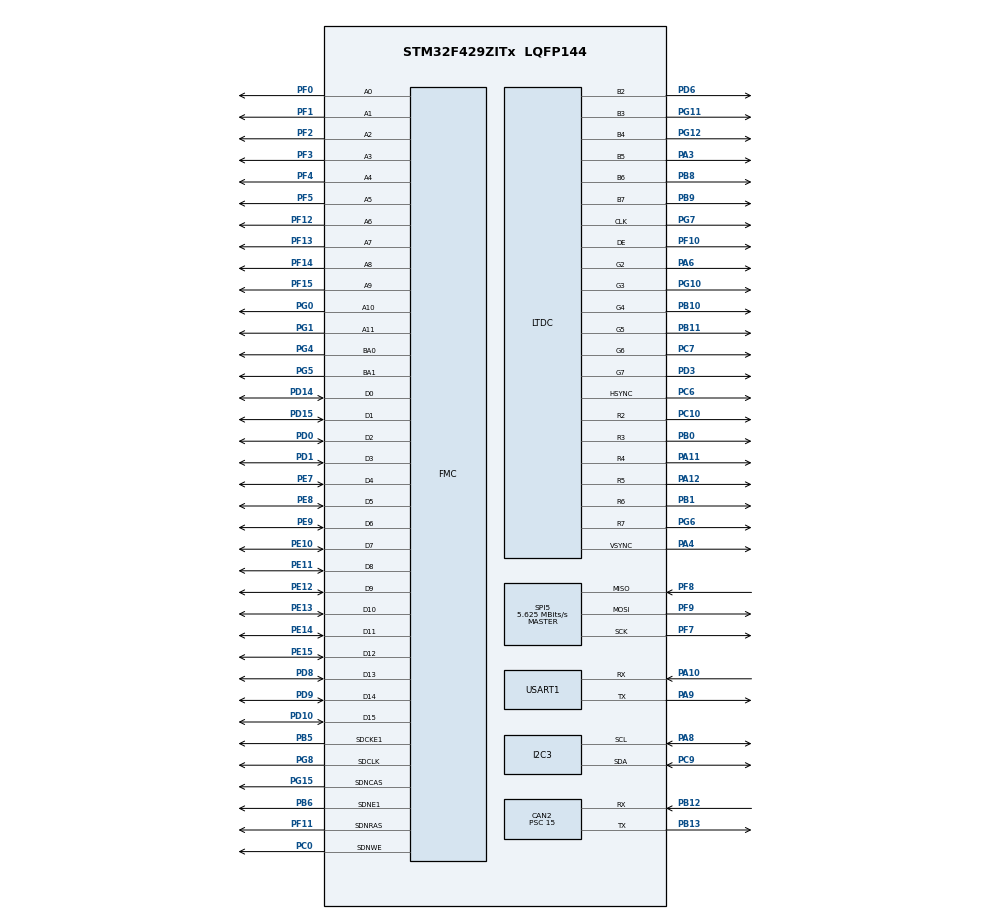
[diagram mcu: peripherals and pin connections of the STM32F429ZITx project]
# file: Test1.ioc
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CAN2.BS1=CAN_BS1_2TQ
CAN2.BS2=CAN_BS2_3TQ
CAN2.CalculateBaudRate=500000
CAN2.CalculateTimeBit=2000
CAN2.CalculateTimeQuantum=333.3333333333333
CAN2.Mode=CAN_MODE_LOOPBACK
CAN2.Prescaler=15
CAN2.SJW=CAN_SJW_4TQ
DMA2D.ColorMode=DMA2D_OUTPUT_RGB565
FMC.CASLatency1=FMC_SDRAM_CAS_LATENCY_3
FMC.ExitSelfRefreshDelay1=7
FMC.LoadToActiveDelay1=2
FMC.RCDDelay1=2
FMC.RPDelay1=2
FMC.RPDelay2=2
FMC.ReadPipeDelay1=FMC_SDRAM_RPIPE_DELAY_1
FMC.ReadPipeDelay2=FMC_SDRAM_RPIPE_DELAY_1
FMC.RowCycleDelay1=7
FMC.RowCycleDelay2=7
FMC.SDClockPeriod1=FMC_SDRAM_CLOCK_PERIOD_2
FMC.SDClockPeriod2=FMC_SDRAM_CLOCK_PERIOD_2
FMC.SelfRefreshTime1=4
FMC.WriteRecoveryTime1=3
LTDC.ActiveH=320
LTDC.ActiveW=240
LTDC.HBP=20
LTDC.HFP=10
LTDC.HSync=10
LTDC.VFP=4
LTDC.VSync=2
Mcu.Family=STM32F4
Mcu.Name=STM32F429ZITx
Mcu.Package=LQFP144
NVIC.CAN2_RX0_IRQn=true\:1\:0\:true\:false\:true\:true\:true\:true
NVIC.CAN2_RX1_IRQn=true\:1\:0\:true\:false\:true\:true\:true\:true
NVIC.DMA2D_IRQn=true\:2\:0\:true\:false\:true\:true\:true\:true
NVIC.LTDC_ER_IRQn=true\:2\:0\:true\:false\:true\:true\:true\:true
NVIC.LTDC_IRQn=true\:2\:0\:true\:false\:true\:true\:true\:true
NVIC.PriorityGroup=NVIC_PRIORITYGROUP_4
PA10.Mode=Asynchronous
PA10.Signal=USART1_RX
PA11.Mode=RGB666
PA11.Signal=LTDC_R4
PA12.Mode=RGB666
PA12.Signal=LTDC_R5
PA3.Mode=RGB666
PA3.Signal=LTDC_B5
PA4.Mode=RGB666
PA4.Signal=LTDC_VSYNC
PA6.Mode=RGB666
PA6.Signal=LTDC_G2
PA8.Mode=I2C
PA8.Signal=I2C3_SCL
PA9.Mode=Asynchronous
PA9.Signal=USART1_TX
PB0.Mode=RGB666
PB0.Signal=LTDC_R3
PB1.Mode=RGB666
PB1.Signal=LTDC_R6
PB10.Mode=RGB666
PB10.Signal=LTDC_G4
PB11.Mode=RGB666
PB11.Signal=LTDC_G5
PB12.Mode=CAN_Activate
PB12.Signal=CAN2_RX
PB13.Mode=CAN_Activate
PB13.Signal=CAN2_TX
PB5.Mode=SdramChipSelect2_1
PB5.Signal=FMC_SDCKE1
PB6.Mode=SdramChipSelect2_1
PB6.Signal=FMC_SDNE1
PB8.Mode=RGB666
PB8.Signal=LTDC_B6
PB9.Mode=RGB666
PB9.Signal=LTDC_B7
PC0.Signal=FMC_SDNWE
PC10.Mode=RGB666
PC10.Signal=LTDC_R2
PC6.Mode=RGB666
PC6.Signal=LTDC_HSYNC
PC7.Mode=RGB666
PC7.Signal=LTDC_G6
PC9.Mode=I2C
PC9.Signal=I2C3_SDA
PD0.Signal=FMC_D2_DA2
PD1.Signal=FMC_D3_DA3
PD10.Signal=FMC_D15_DA15
PD14.Signal=FMC_D0_DA0
PD15.Signal=FMC_D1_DA1
PD3.Mode=RGB666
PD3.Signal=LTDC_G7
PD6.Mode=RGB666
PD6.Signal=LTDC_B2
PD8.Signal=FMC_D13_DA13
PD9.Signal=FMC_D14_DA14
PE10.Signal=FMC_D7_DA7
PE11.Signal=FMC_D8_DA8
PE12.Signal=FMC_D9_DA9
PE13.Signal=FMC_D10_DA10
PE14.Signal=FMC_D11_DA11
PE15.Signal=FMC_D12_DA12
PE7.Signal=FMC_D4_DA4
PE8.Signal=FMC_D5_DA5
PE9.Signal=FMC_D6_DA6
PF0.Signal=FMC_A0
PF1.Signal=FMC_A1
PF10.Mode=RGB666
PF10.Signal=LTDC_DE
PF11.Signal=FMC_SDNRAS
PF12.Signal=FMC_A6
PF13.Signal=FMC_A7
PF14.Signal=FMC_A8
PF15.Signal=FMC_A9
PF2.Signal=FMC_A2
PF3.Signal=FMC_A3
PF4.Signal=FMC_A4
PF5.Signal=FMC_A5
PF7.Mode=Full_Duplex_Master
PF7.Signal=SPI5_SCK
PF8.Mode=Full_Duplex_Master
PF8.Signal=SPI5_MISO
PF9.Mode=Full_Duplex_Master
PF9.Signal=SPI5_MOSI
PG0.Signal=FMC_A10
PG1.Signal=FMC_A11
PG10.Mode=RGB666
PG10.Signal=LTDC_G3
PG11.Mode=RGB666
PG11.Signal=LTDC_B3
PG12.Mode=RGB666
PG12.Signal=LTDC_B4
PG15.Signal=FMC_SDNCAS
PG4.Signal=FMC_A14_BA0
PG5.Signal=FMC_A15_BA1
PG6.Mode=RGB666
PG6.Signal=LTDC_R7
PG7.Mode=RGB666
PG7.Signal=LTDC_CLK
PG8.Signal=FMC_SDCLK
PH0/OSC_IN.Mode=HSE-External-Oscillator
PH0/OSC_IN.Signal=RCC_OSC_IN
PH1/OSC_OUT.Mode=HSE-External-Oscillator
PH1/OSC_OUT.Signal=RCC_OSC_OUT
ProjectManager.HeapSize=0x200
ProjectManager.StackSize=0x400
ProjectManager.TargetToolchain=STM32CubeIDE
RCC.48MHZClocksFreq_Value=120000000
RCC.AHBFreq_Value=180000000
RCC.APB1CLKDivider=RCC_HCLK_DIV4
RCC.APB1Freq_Value=45000000
RCC.APB1TimFreq_Value=90000000
RCC.APB2CLKDivider=RCC_HCLK_DIV2
RCC.APB2Freq_Value=90000000
RCC.APB2TimFreq_Value=180000000
RCC.CortexFreq_Value=180000000
RCC.HCLKFreq_Value=180000000
RCC.HSE_VALUE=8000000
RCC.HSI_VALUE=16000000
RCC.LSE_VALUE=32768
RCC.PLLN=180
RCC.PLLQ=3
RCC.PLLSAIN=52
RCC.PLLSAIR=4
RCC.PLLSourceVirtual=RCC_PLLSOURCE_HSE
RCC.SYSCLKFreq_VALUE=180000000
RCC.SYSCLKSource=RCC_SYSCLKSOURCE_PLLCLK
RCC.VCOOutputFreq_Value=360000000
SH.FMC_A0.0=FMC_A0,12b-sda1
SH.FMC_A1.0=FMC_A1,12b-sda1
SH.FMC_A10.0=FMC_A10,12b-sda1
SH.FMC_A11.0=FMC_A11,12b-sda1
SH.FMC_A14_BA0.0=FMC_BA0,FourSdramBanks1
SH.FMC_A15_BA1.0=FMC_BA1,FourSdramBanks1
SH.FMC_A2.0=FMC_A2,12b-sda1
SH.FMC_A3.0=FMC_A3,12b-sda1
SH.FMC_A4.0=FMC_A4,12b-sda1
SH.FMC_A5.0=FMC_A5,12b-sda1
SH.FMC_A6.0=FMC_A6,12b-sda1
SH.FMC_A7.0=FMC_A7,12b-sda1
SH.FMC_A8.0=FMC_A8,12b-sda1
SH.FMC_A9.0=FMC_A9,12b-sda1
SH.FMC_D0_DA0.0=FMC_D0,sd-16b-d1
SH.FMC_D10_DA10.0=FMC_D10,sd-16b-d1
SH.FMC_D11_DA11.0=FMC_D11,sd-16b-d1
SH.FMC_D12_DA12.0=FMC_D12,sd-16b-d1
SH.FMC_D13_DA13.0=FMC_D13,sd-16b-d1
SH.FMC_D14_DA14.0=FMC_D14,sd-16b-d1
SH.FMC_D15_DA15.0=FMC_D15,sd-16b-d1
SH.FMC_D1_DA1.0=FMC_D1,sd-16b-d1
SH.FMC_D2_DA2.0=FMC_D2,sd-16b-d1
SH.FMC_D3_DA3.0=FMC_D3,sd-16b-d1
SH.FMC_D4_DA4.0=FMC_D4,sd-16b-d1
SH.FMC_D5_DA5.0=FMC_D5,sd-16b-d1
SH.FMC_D6_DA6.0=FMC_D6,sd-16b-d1
SH.FMC_D7_DA7.0=FMC_D7,sd-16b-d1
SH.FMC_D8_DA8.0=FMC_D8,sd-16b-d1
SH.FMC_D9_DA9.0=FMC_D9,sd-16b-d1
SH.FMC_SDCLK.0=FMC_SDCLK,12b-sda1
SH.FMC_SDNCAS.0=FMC_SDNCAS,12b-sda1
SH.FMC_SDNRAS.0=FMC_SDNRAS,12b-sda1
SH.FMC_SDNWE.0=FMC_SDNWE,12b-sda1
SPI5.BaudRatePrescaler=SPI_BAUDRATEPRESCALER_16
SPI5.CalculateBaudRate=5.625 MBits/s
SPI5.Direction=SPI_DIRECTION_2LINES
SPI5.Mode=SPI_MODE_MASTER
SPI5.VirtualType=VM_MASTER
USART1.VirtualMode=VM_ASYNC
VP_DMA2D_VS_DMA2D.Mode=DMA2D_Activate
board=STM32F429I-DISC1

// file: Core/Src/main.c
/* USER CODE BEGIN Header */
/**
  ******************************************************************************
  * @file           : main.c
  * @brief          : Main program body
  ******************************************************************************
  * @attention
  *
  * Copyright (c) 2023 STMicroelectronics.
  * All rights reserved.
  *
  * This software is licensed under terms that can be found in the LICENSE file
  * in the root directory of this software component.
  * If no LICENSE file comes with this software, it is provided AS-IS.
  *
  ******************************************************************************
  */
/* USER CODE END Header */
#include "main.h"

/* USER CODE BEGIN Includes */
#include "stm32f429i_discovery_lcd.h"
#include "image.h"
/* USER CODE END Includes */

CAN_HandleTypeDef hcan2;

DMA2D_HandleTypeDef hdma2d;

I2C_HandleTypeDef hi2c3;

LTDC_HandleTypeDef hltdc;

SPI_HandleTypeDef hspi5;

UART_HandleTypeDef huart1;

SDRAM_HandleTypeDef hsdram1;

void SystemClock_Config(void);
static void MX_GPIO_Init(void);
static void MX_DMA2D_Init(void);
static void MX_FMC_Init(void);
static void MX_I2C3_Init(void);
static void MX_LTDC_Init(void);
static void MX_SPI5_Init(void);
static void MX_USART1_UART_Init(void);
static void MX_CAN2_Init(void);

/* USER CODE BEGIN 0 */
CAN_TxHeaderTypeDef TxHeader;
CAN_RxHeaderTypeDef RxHeader;

uint8_t TxData[8] = { 'X' , 'A' , 'T' , 'F', 'D' , 'D' , 'G' , 'D' };

uint8_t RxData[8];

uint32_t TxMailbox;

void HAL_CAN_RxFifo0MsgPendingCallback(CAN_HandleTypeDef *hcan)
{
	HAL_CAN_GetRxMessage(&hcan2, CAN_RX_FIFO0, &RxHeader, RxData);
}

/* USER CODE END 0 */

int main(void)
{

  /* MCU Configuration--------------------------------------------------------*/

  /* Reset of all peripherals, Initializes the Flash interface and the Systick. */
  HAL_Init();

  /* Configure the system clock */
  SystemClock_Config();

  /* Initialize all configured peripherals */
  MX_GPIO_Init();
  MX_DMA2D_Init();
  MX_FMC_Init();
  MX_I2C3_Init();
  MX_LTDC_Init();
  MX_SPI5_Init();
  MX_USART1_UART_Init();
  MX_CAN2_Init();
  /* USER CODE BEGIN 2 */

	HAL_CAN_Start(&hcan2);

	  // Activate the notification
	HAL_CAN_ActivateNotification(&hcan2, CAN_IT_RX_FIFO0_MSG_PENDING);

	TxHeader.DLC = 8;  // data length
	TxHeader.IDE = CAN_ID_STD;
	TxHeader.StdId = 0x407;  // ID

	BSP_LCD_Init();
	BSP_LCD_LayerDefaultInit(LCD_BACKGROUND_LAYER,LCD_FRAME_BUFFER);
	BSP_LCD_LayerDefaultInit(LCD_FOREGROUND_LAYER,LCD_FRAME_BUFFER);
	BSP_LCD_SelectLayer(LCD_FOREGROUND_LAYER);
	BSP_LCD_SetFont(&Font20);
	BSP_LCD_DisplayOn();
	BSP_LCD_Clear(LCD_COLOR_BLUE);

	BSP_LCD_SetTextColor(LCD_COLOR_RED);
	BSP_LCD_DisplayStringAt(1 , 125 ,(uint8_t *) "CAN DATA:",LEFT_MODE);

	uint16_t x = 24;
  /* USER CODE END 2 */

  /* Infinite loop */
  while (1)
  {

    /* USER CODE BEGIN 3 */
	  HAL_CAN_AddTxMessage(&hcan2, &TxHeader, TxData, &TxMailbox);
	  BSP_LCD_SetTextColor(LCD_COLOR_RED);
	  for (uint32_t i = 0; i < 8 ; i ++)
	  {
		  BSP_LCD_DisplayChar (x , 150 , RxData[i]);
		  x+= 24;
	  }
	  x = 24;

  }
  /* USER CODE END 3 */
}

void SystemClock_Config(void)
{
  RCC_OscInitTypeDef RCC_OscInitStruct = {0};
  RCC_ClkInitTypeDef RCC_ClkInitStruct = {0};

  /** Configure the main internal regulator output voltage
  */
  __HAL_RCC_PWR_CLK_ENABLE();
  __HAL_PWR_VOLTAGESCALING_CONFIG(PWR_REGULATOR_VOLTAGE_SCALE1);

  /** Initializes the RCC Oscillators according to the specified parameters
  * in the RCC_OscInitTypeDef structure.
  */
  RCC_OscInitStruct.OscillatorType = RCC_OSCILLATORTYPE_HSE;
  RCC_OscInitStruct.HSEState = RCC_HSE_ON;
  RCC_OscInitStruct.PLL.PLLState = RCC_PLL_ON;
  RCC_OscInitStruct.PLL.PLLSource = RCC_PLLSOURCE_HSE;
  RCC_OscInitStruct.PLL.PLLM = 16;
  RCC_OscInitStruct.PLL.PLLN = 180;
  RCC_OscInitStruct.PLL.PLLP = RCC_PLLP_DIV2;
  RCC_OscInitStruct.PLL.PLLQ = 3;
  if (HAL_RCC_OscConfig(&RCC_OscInitStruct) != HAL_OK)
  {
    Error_Handler();
  }

  /** Activate the Over-Drive mode
  */
  if (HAL_PWREx_EnableOverDrive() != HAL_OK)
  {
    Error_Handler();
  }

  /** Initializes the CPU, AHB and APB buses clocks
  */
  RCC_ClkInitStruct.ClockType = RCC_CLOCKTYPE_HCLK|RCC_CLOCKTYPE_SYSCLK
                              |RCC_CLOCKTYPE_PCLK1|RCC_CLOCKTYPE_PCLK2;
  RCC_ClkInitStruct.SYSCLKSource = RCC_SYSCLKSOURCE_PLLCLK;
  RCC_ClkInitStruct.AHBCLKDivider = RCC_SYSCLK_DIV1;
  RCC_ClkInitStruct.APB1CLKDivider = RCC_HCLK_DIV4;
  RCC_ClkInitStruct.APB2CLKDivider = RCC_HCLK_DIV2;

  if (HAL_RCC_ClockConfig(&RCC_ClkInitStruct, FLASH_LATENCY_5) != HAL_OK)
  {
    Error_Handler();
  }
}

static void MX_CAN2_Init(void)
{

  hcan2.Instance = CAN2;
  hcan2.Init.Prescaler = 15;
  hcan2.Init.Mode = CAN_MODE_LOOPBACK;
  hcan2.Init.SyncJumpWidth = CAN_SJW_4TQ;
  hcan2.Init.TimeSeg1 = CAN_BS1_2TQ;
  hcan2.Init.TimeSeg2 = CAN_BS2_3TQ;
  hcan2.Init.TimeTriggeredMode = DISABLE;
  hcan2.Init.AutoBusOff = DISABLE;
  hcan2.Init.AutoWakeUp = DISABLE;
  hcan2.Init.AutoRetransmission = DISABLE;
  hcan2.Init.ReceiveFifoLocked = DISABLE;
  hcan2.Init.TransmitFifoPriority = DISABLE;
  if (HAL_CAN_Init(&hcan2) != HAL_OK)
  {
    Error_Handler();
  }
  /* USER CODE BEGIN CAN2_Init 2 */
  CAN_FilterTypeDef canfilterconfig;

  canfilterconfig.FilterActivation = CAN_FILTER_ENABLE;
  canfilterconfig.FilterBank = 18;  // which filter bank to use from the assigned ones
  canfilterconfig.FilterFIFOAssignment = CAN_FILTER_FIFO0;
  canfilterconfig.FilterIdHigh = 0x407<<5;
  canfilterconfig.FilterIdLow = 0;
  canfilterconfig.FilterMaskIdHigh = 0x407<<5;
  canfilterconfig.FilterMaskIdLow = 0x0000;
  canfilterconfig.FilterMode = CAN_FILTERMODE_IDMASK;
  canfilterconfig.FilterScale = CAN_FILTERSCALE_32BIT;
 // canfilterconfig.SlaveStartFilterBank = 20;  // how many filters to assign to the CAN1 (master can)

  HAL_CAN_ConfigFilter(&hcan2, &canfilterconfig);
  /* USER CODE END CAN2_Init 2 */

}

static void MX_DMA2D_Init(void)
{

  hdma2d.Instance = DMA2D;
  hdma2d.Init.Mode = DMA2D_M2M;
  hdma2d.Init.ColorMode = DMA2D_OUTPUT_RGB565;
  hdma2d.Init.OutputOffset = 0;
  hdma2d.LayerCfg[1].InputOffset = 0;
  hdma2d.LayerCfg[1].InputColorMode = DMA2D_INPUT_RGB565;
  hdma2d.LayerCfg[1].AlphaMode = DMA2D_NO_MODIF_ALPHA;
  hdma2d.LayerCfg[1].InputAlpha = 0;
  if (HAL_DMA2D_Init(&hdma2d) != HAL_OK)
  {
    Error_Handler();
  }
  if (HAL_DMA2D_ConfigLayer(&hdma2d, 1) != HAL_OK)
  {
    Error_Handler();
  }

}

static void MX_I2C3_Init(void)
{

  hi2c3.Instance = I2C3;
  hi2c3.Init.ClockSpeed = 100000;
  hi2c3.Init.DutyCycle = I2C_DUTYCYCLE_2;
  hi2c3.Init.OwnAddress1 = 0;
  hi2c3.Init.AddressingMode = I2C_ADDRESSINGMODE_7BIT;
  hi2c3.Init.DualAddressMode = I2C_DUALADDRESS_DISABLE;
  hi2c3.Init.OwnAddress2 = 0;
  hi2c3.Init.GeneralCallMode = I2C_GENERALCALL_DISABLE;
  hi2c3.Init.NoStretchMode = I2C_NOSTRETCH_DISABLE;
  if (HAL_I2C_Init(&hi2c3) != HAL_OK)
  {
    Error_Handler();
  }

  /** Configure Analogue filter
  */
  if (HAL_I2CEx_ConfigAnalogFilter(&hi2c3, I2C_ANALOGFILTER_ENABLE) != HAL_OK)
  {
    Error_Handler();
  }

  /** Configure Digital filter
  */
  if (HAL_I2CEx_ConfigDigitalFilter(&hi2c3, 0) != HAL_OK)
  {
    Error_Handler();
  }

}

static void MX_LTDC_Init(void)
{

  LTDC_LayerCfgTypeDef pLayerCfg = {0};
  LTDC_LayerCfgTypeDef pLayerCfg1 = {0};

  hltdc.Instance = LTDC;
  hltdc.Init.HSPolarity = LTDC_HSPOLARITY_AL;
  hltdc.Init.VSPolarity = LTDC_VSPOLARITY_AL;
  hltdc.Init.DEPolarity = LTDC_DEPOLARITY_AL;
  hltdc.Init.PCPolarity = LTDC_PCPOLARITY_IPC;
  hltdc.Init.HorizontalSync = 9;
  hltdc.Init.VerticalSync = 1;
  hltdc.Init.AccumulatedHBP = 29;
  hltdc.Init.AccumulatedVBP = 3;
  hltdc.Init.AccumulatedActiveW = 269;
  hltdc.Init.AccumulatedActiveH = 323;
  hltdc.Init.TotalWidth = 279;
  hltdc.Init.TotalHeigh = 327;
  hltdc.Init.Backcolor.Blue = 0;
  hltdc.Init.Backcolor.Green = 0;
  hltdc.Init.Backcolor.Red = 0;
  if (HAL_LTDC_Init(&hltdc) != HAL_OK)
  {
    Error_Handler();
  }
  pLayerCfg.WindowX0 = 0;
  pLayerCfg.WindowX1 = 0;
  pLayerCfg.WindowY0 = 0;
  pLayerCfg.WindowY1 = 0;
  pLayerCfg.PixelFormat = LTDC_PIXEL_FORMAT_ARGB8888;
  pLayerCfg.Alpha = 0;
  pLayerCfg.Alpha0 = 0;
  pLayerCfg.BlendingFactor1 = LTDC_BLENDING_FACTOR1_CA;
  pLayerCfg.BlendingFactor2 = LTDC_BLENDING_FACTOR2_CA;
  pLayerCfg.FBStartAdress = 0;
  pLayerCfg.ImageWidth = 0;
  pLayerCfg.ImageHeight = 0;
  pLayerCfg.Backcolor.Blue = 0;
  pLayerCfg.Backcolor.Green = 0;
  pLayerCfg.Backcolor.Red = 0;
  if (HAL_LTDC_ConfigLayer(&hltdc, &pLayerCfg, 0) != HAL_OK)
  {
    Error_Handler();
  }
  pLayerCfg1.WindowX0 = 0;
  pLayerCfg1.WindowX1 = 0;
  pLayerCfg1.WindowY0 = 0;
  pLayerCfg1.WindowY1 = 0;
  pLayerCfg1.PixelFormat = LTDC_PIXEL_FORMAT_ARGB8888;
  pLayerCfg1.Alpha = 0;
  pLayerCfg1.Alpha0 = 0;
  pLayerCfg1.BlendingFactor1 = LTDC_BLENDING_FACTOR1_CA;
  pLayerCfg1.BlendingFactor2 = LTDC_BLENDING_FACTOR2_CA;
  pLayerCfg1.FBStartAdress = 0;
  pLayerCfg1.ImageWidth = 0;
  pLayerCfg1.ImageHeight = 0;
  pLayerCfg1.Backcolor.Blue = 0;
  pLayerCfg1.Backcolor.Green = 0;
  pLayerCfg1.Backcolor.Red = 0;
  if (HAL_LTDC_ConfigLayer(&hltdc, &pLayerCfg1, 1) != HAL_OK)
  {
    Error_Handler();
  }

}

static void MX_SPI5_Init(void)
{

  /* SPI5 parameter configuration*/
  hspi5.Instance = SPI5;
  hspi5.Init.Mode = SPI_MODE_MASTER;
  hspi5.Init.Direction = SPI_DIRECTION_2LINES;
  hspi5.Init.DataSize = SPI_DATASIZE_8BIT;
  hspi5.Init.CLKPolarity = SPI_POLARITY_LOW;
  hspi5.Init.CLKPhase = SPI_PHASE_1EDGE;
  hspi5.Init.NSS = SPI_NSS_SOFT;
  hspi5.Init.BaudRatePrescaler = SPI_BAUDRATEPRESCALER_16;
  hspi5.Init.FirstBit = SPI_FIRSTBIT_MSB;
  hspi5.Init.TIMode = SPI_TIMODE_DISABLE;
  hspi5.Init.CRCCalculation = SPI_CRCCALCULATION_DISABLE;
  hspi5.Init.CRCPolynomial = 10;
  if (HAL_SPI_Init(&hspi5) != HAL_OK)
  {
    Error_Handler();
  }

}

static void MX_USART1_UART_Init(void)
{

  huart1.Instance = USART1;
  huart1.Init.BaudRate = 115200;
  huart1.Init.WordLength = UART_WORDLENGTH_8B;
  huart1.Init.StopBits = UART_STOPBITS_1;
  huart1.Init.Parity = UART_PARITY_NONE;
  huart1.Init.Mode = UART_MODE_TX_RX;
  huart1.Init.HwFlowCtl = UART_HWCONTROL_NONE;
  huart1.Init.OverSampling = UART_OVERSAMPLING_16;
  if (HAL_UART_Init(&huart1) != HAL_OK)
  {
    Error_Handler();
  }

}

/* FMC initialization function */
static void MX_FMC_Init(void)
{

  FMC_SDRAM_TimingTypeDef SdramTiming = {0};

  /** Perform the SDRAM1 memory initialization sequence
  */
  hsdram1.Instance = FMC_SDRAM_DEVICE;
  /* hsdram1.Init */
  hsdram1.Init.SDBank = FMC_SDRAM_BANK2;
  hsdram1.Init.ColumnBitsNumber = FMC_SDRAM_COLUMN_BITS_NUM_8;
  hsdram1.Init.RowBitsNumber = FMC_SDRAM_ROW_BITS_NUM_12;
  hsdram1.Init.MemoryDataWidth = FMC_SDRAM_MEM_BUS_WIDTH_16;
  hsdram1.Init.InternalBankNumber = FMC_SDRAM_INTERN_BANKS_NUM_4;
  hsdram1.Init.CASLatency = FMC_SDRAM_CAS_LATENCY_3;
  hsdram1.Init.WriteProtection = FMC_SDRAM_WRITE_PROTECTION_DISABLE;
  hsdram1.Init.SDClockPeriod = FMC_SDRAM_CLOCK_PERIOD_2;
  hsdram1.Init.ReadBurst = FMC_SDRAM_RBURST_DISABLE;
  hsdram1.Init.ReadPipeDelay = FMC_SDRAM_RPIPE_DELAY_1;
  /* SdramTiming */
  SdramTiming.LoadToActiveDelay = 2;
  SdramTiming.ExitSelfRefreshDelay = 7;
  SdramTiming.SelfRefreshTime = 4;
  SdramTiming.RowCycleDelay = 7;
  SdramTiming.WriteRecoveryTime = 3;
  SdramTiming.RPDelay = 2;
  SdramTiming.RCDDelay = 2;

  if (HAL_SDRAM_Init(&hsdram1, &SdramTiming) != HAL_OK)
  {
    Error_Handler( );
  }

}

static void MX_GPIO_Init(void)
{

  /* GPIO Ports Clock Enable */
  __HAL_RCC_GPIOF_CLK_ENABLE();
  __HAL_RCC_GPIOH_CLK_ENABLE();
  __HAL_RCC_GPIOC_CLK_ENABLE();
  __HAL_RCC_GPIOA_CLK_ENABLE();
  __HAL_RCC_GPIOB_CLK_ENABLE();
  __HAL_RCC_GPIOG_CLK_ENABLE();
  __HAL_RCC_GPIOE_CLK_ENABLE();
  __HAL_RCC_GPIOD_CLK_ENABLE();

}

void Error_Handler(void)
{
  __disable_irq();
  while (1)
  {
  }
}
